VERSION 5.8 ;
BUSBITCHARS "[]" ;
DIVIDERCHAR "/" ;

UNITS
  DATABASE MICRONS 1000 ;
END UNITS

MANUFACTURINGGRID 0.005 ;

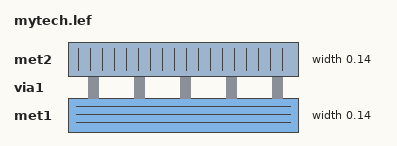
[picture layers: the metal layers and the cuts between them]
LAYER met1
  TYPE ROUTING ;
  DIRECTION HORIZONTAL ;
  WIDTH 0.14 ;
END met1

LAYER via1
  TYPE CUT ;
END via1

LAYER met2
  TYPE ROUTING ;
  DIRECTION VERTICAL ;
  WIDTH 0.14 ;
END met2

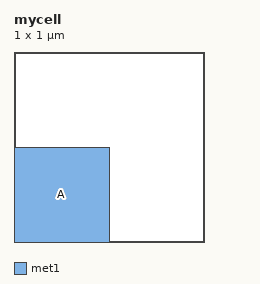
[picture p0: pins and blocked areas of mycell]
MACRO mycell
  CLASS CORE ;
  ORIGIN 0 0 ;
  SIZE 1.000 BY 1.000 ;
  PIN A
    DIRECTION INPUT ;
    PORT
      LAYER met1 ;
        RECT 0.000 0.000 0.500 0.500 ;
    END
  END A
END mycell

MACRO abut
  CLASS CORE ;
  ORIGIN 0 0 ;
  SIZE 0.500 BY 0.500 ;
  OBS
    LAYER met1 ;
      RECT 0.000 0.000 0.500 0.500 ;
  END
END abut

END LIBRARY
